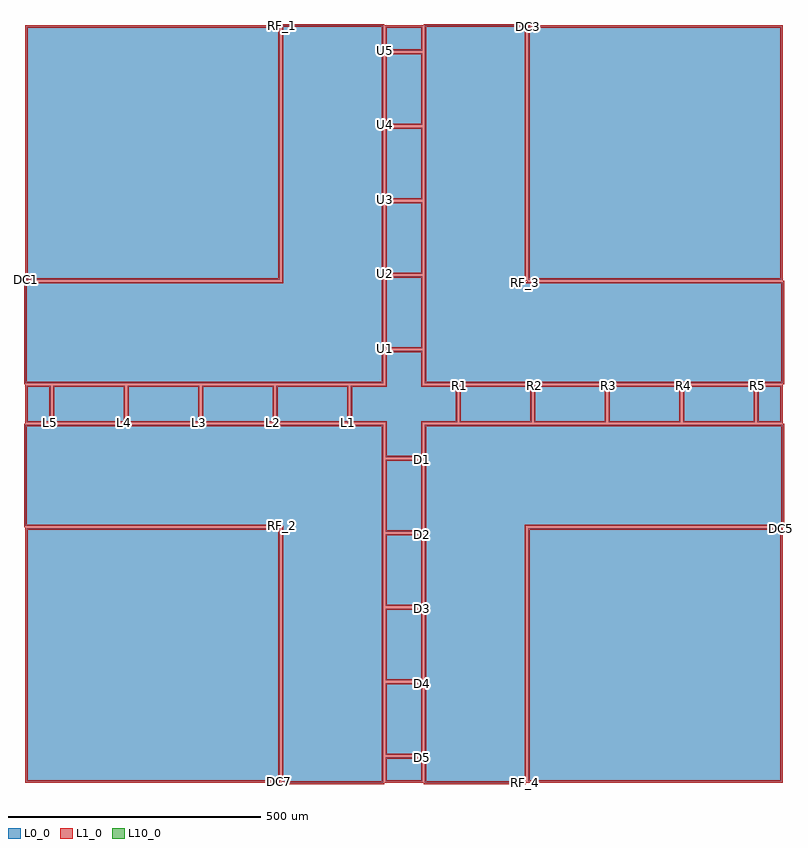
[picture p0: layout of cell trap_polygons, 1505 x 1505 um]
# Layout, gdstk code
import gdstk
lib = gdstk.Library(unit=1e-6, precision=1e-09)
def P(c, l, *ps):  # polygons
    for p in ps: c.add(gdstk.Polygon(p, *l))
L0_0 = (0, 0)
L1_0 = (1, 0)
L10_0 = (10, 0)

trap_polygons = lib.new_cell('trap_polygons')
P(trap_polygons, L0_0, [(-246.5,-747.5),(-747.5,-747.5),(-747.5,-246.5),(-246.5,-246.5),(-246.5,-747.5)],
  [(747.5,-246.5),(747.5,-747.5),(246.5,-747.5),(246.5,-246.5),(747.5,-246.5)],
  [(246.5,747.5),(747.5,747.5),(747.5,246.5),(246.5,246.5),(246.5,747.5)],
  [(-747.5,246.5),(-747.5,747.5),(-246.5,747.5),(-246.5,246.5),(-747.5,246.5)],
  [(-36.5,700),(-36.5,747.5),(36.5,747.5),(36.5,700),(-36.5,700)],
  [(700,36.5),(747.5,36.5),(747.5,-36.5),(700,-36.5),(700,36.5)],
  [(36.5,-700),(36.5,-747.5),(-36.5,-747.5),(-36.5,-700),(36.5,-700)],
  [(-700,-36.5),(-747.5,-36.5),(-747.5,36.5),(-700,36.5),(-700,-36.5)],
  [(-36.5,552.5),(-36.5,695),(36.5,695),(36.5,552.5),(-36.5,552.5)],
  [(552.5,36.5),(695,36.5),(695,-36.5),(552.5,-36.5),(552.5,36.5)],
  [(36.5,-552.5),(36.5,-695),(-36.5,-695),(-36.5,-552.5),(36.5,-552.5)],
  [(-552.5,-36.5),(-695,-36.5),(-695,36.5),(-552.5,36.5),(-552.5,-36.5)],
  [(-36.5,405),(-36.5,547.5),(36.5,547.5),(36.5,405),(-36.5,405)],
  [(405,36.5),(547.5,36.5),(547.5,-36.5),(405,-36.5),(405,36.5)],
  [(36.5,-405),(36.5,-547.5),(-36.5,-547.5),(-36.5,-405),(36.5,-405)],
  [(-405,-36.5),(-547.5,-36.5),(-547.5,36.5),(-405,36.5),(-405,-36.5)],
  [(-36.5,257.5),(-36.5,400),(36.5,400),(36.5,257.5),(-36.5,257.5)],
  [(257.5,36.5),(400,36.5),(400,-36.5),(257.5,-36.5),(257.5,36.5)],
  [(36.5,-257.5),(36.5,-400),(-36.5,-400),(-36.5,-257.5),(36.5,-257.5)],
  [(-257.5,-36.5),(-400,-36.5),(-400,36.5),(-257.5,36.5),(-257.5,-36.5)],
  [(-36.5,110),(-36.5,252.5),(36.5,252.5),(36.5,110),(-36.5,110)],
  [(110,36.5),(252.5,36.5),(252.5,-36.5),(110,-36.5),(110,36.5)],
  [(36.5,-110),(36.5,-252.5),(-36.5,-252.5),(-36.5,-110),(36.5,-110)],
  [(-110,-36.5),(-252.5,-36.5),(-252.5,36.5),(-110,36.5),(-110,-36.5)],
  [(-36.5,105),(36.5,105),(36.5,36.5),(105,36.5),(105,-36.5),(36.5,-36.5),(36.5,-105),(-36.5,-105),(-36.5,-36.5),(-105,-36.5),(-105,36.5),(-36.5,36.5),(-36.5,105)],
  [(241.5,-750),(41.5,-750),(41.5,-41.5),(750,-41.5),(750,-241.5),(241.5,-241.5),(241.5,-750)],
  [(241.5,241.5),(750,241.5),(750,41.5),(41.5,41.5),(41.5,750),(241.5,750),(241.5,241.5)],
  [(-241.5,-241.5),(-750,-241.5),(-750,-41.5),(-41.5,-41.5),(-41.5,-750),(-241.5,-750),(-241.5,-241.5)],
  [(-241.5,750),(-41.5,750),(-41.5,41.5),(-750,41.5),(-750,241.5),(-241.5,241.5),(-241.5,750)])
P(trap_polygons, L1_0, [(-246.5,-750),(-246.5,-745),(-745,-745),(-745,-249),(-249,-249),(-249,-747.5),(-244,-747.5),(-244,-244),(-750,-244),(-750,-750)],
  [(750,-246.5),(745,-246.5),(745,-745),(249,-745),(249,-249),(747.5,-249),(747.5,-244),(244,-244),(244,-750),(750,-750)],
  [(246.5,750),(246.5,745),(745,745),(745,249),(249,249),(249,747.5),(244,747.5),(244,244),(750,244),(750,750)],
  [(-750,246.5),(-745,246.5),(-745,745),(-249,745),(-249,249),(-747.5,249),(-747.5,244),(-244,244),(-244,750),(-750,750)],
  [(-39,700),(-34,700),(-34,745),(34,745),(34,702.5),(-36.5,702.5),(-36.5,697.5),(39,697.5),(39,750),(-39,750)],
  [(700,39),(700,34),(745,34),(745,-34),(702.5,-34),(702.5,36.5),(697.5,36.5),(697.5,-39),(750,-39),(750,39)],
  [(39,-700),(34,-700),(34,-745),(-34,-745),(-34,-702.5),(36.5,-702.5),(36.5,-697.5),(-39,-697.5),(-39,-750),(39,-750)],
  [(-700,-39),(-700,-34),(-745,-34),(-745,34),(-702.5,34),(-702.5,-36.5),(-697.5,-36.5),(-697.5,39),(-750,39),(-750,-39)],
  [(-39,552.5),(-34,552.5),(-34,692.5),(34,692.5),(34,555),(-36.5,555),(-36.5,550),(39,550),(39,697.5),(-39,697.5)],
  [(552.5,39),(552.5,34),(692.5,34),(692.5,-34),(555,-34),(555,36.5),(550,36.5),(550,-39),(697.5,-39),(697.5,39)],
  [(39,-552.5),(34,-552.5),(34,-692.5),(-34,-692.5),(-34,-555),(36.5,-555),(36.5,-550),(-39,-550),(-39,-697.5),(39,-697.5)],
  [(-552.5,-39),(-552.5,-34),(-692.5,-34),(-692.5,34),(-555,34),(-555,-36.5),(-550,-36.5),(-550,39),(-697.5,39),(-697.5,-39)],
  [(-39,405),(-34,405),(-34,545),(34,545),(34,407.5),(-36.5,407.5),(-36.5,402.5),(39,402.5),(39,550),(-39,550)],
  [(405,39),(405,34),(545,34),(545,-34),(407.5,-34),(407.5,36.5),(402.5,36.5),(402.5,-39),(550,-39),(550,39)],
  [(39,-405),(34,-405),(34,-545),(-34,-545),(-34,-407.5),(36.5,-407.5),(36.5,-402.5),(-39,-402.5),(-39,-550),(39,-550)],
  [(-405,-39),(-405,-34),(-545,-34),(-545,34),(-407.5,34),(-407.5,-36.5),(-402.5,-36.5),(-402.5,39),(-550,39),(-550,-39)],
  [(-39,257.5),(-34,257.5),(-34,397.5),(34,397.5),(34,260),(-36.5,260),(-36.5,255),(39,255),(39,402.5),(-39,402.5)],
  [(257.5,39),(257.5,34),(397.5,34),(397.5,-34),(260,-34),(260,36.5),(255,36.5),(255,-39),(402.5,-39),(402.5,39)],
  [(39,-257.5),(34,-257.5),(34,-397.5),(-34,-397.5),(-34,-260),(36.5,-260),(36.5,-255),(-39,-255),(-39,-402.5),(39,-402.5)],
  [(-257.5,-39),(-257.5,-34),(-397.5,-34),(-397.5,34),(-260,34),(-260,-36.5),(-255,-36.5),(-255,39),(-402.5,39),(-402.5,-39)],
  [(-39,110),(-34,110),(-34,250),(34,250),(34,112.5),(-36.5,112.5),(-36.5,107.5),(39,107.5),(39,255),(-39,255)],
  [(110,39),(110,34),(250,34),(250,-34),(112.5,-34),(112.5,36.5),(107.5,36.5),(107.5,-39),(255,-39),(255,39)],
  [(39,-110),(34,-110),(34,-250),(-34,-250),(-34,-112.5),(36.5,-112.5),(36.5,-107.5),(-39,-107.5),(-39,-255),(39,-255)],
  [(-110,-39),(-110,-34),(-250,-34),(-250,34),(-112.5,34),(-112.5,-36.5),(-107.5,-36.5),(-107.5,39),(-255,39),(-255,-39)],
  [(-36.5,107.5),(-36.5,102.5),(34,102.5),(34,34),(102.5,34),(102.5,-34),(34,-34),(34,-102.5),(-34,-102.5),(-34,-34),(-102.5,-34),(-102.5,34),(-34,34),(-34,105),(-39,105),(-39,39),(-107.5,39),(-107.5,-39),(-39,-39),(-39,-107.5),(39,-107.5),(39,-39),(107.5,-39),(107.5,39),(39,39),(39,107.5)],
  [(241.5,-752.5),(241.5,-747.5),(44,-747.5),(44,-44),(747.5,-44),(747.5,-239),(239,-239),(239,-750),(244,-750),(244,-244),(752.5,-244),(752.5,-39),(39,-39),(39,-752.5)],
  [(241.5,244),(241.5,239),(747.5,239),(747.5,44),(44,44),(44,747.5),(239,747.5),(239,241.5),(244,241.5),(244,752.5),(39,752.5),(39,39),(752.5,39),(752.5,244)],
  [(-241.5,-244),(-241.5,-239),(-747.5,-239),(-747.5,-44),(-44,-44),(-44,-747.5),(-239,-747.5),(-239,-241.5),(-244,-241.5),(-244,-752.5),(-39,-752.5),(-39,-39),(-752.5,-39),(-752.5,-244)],
  [(-241.5,752.5),(-241.5,747.5),(-44,747.5),(-44,44),(-747.5,44),(-747.5,239),(-239,239),(-239,750),(-244,750),(-244,244),(-752.5,244),(-752.5,39),(-39,39),(-39,752.5)])
P(trap_polygons, L10_0, [(0,0),(0,0),(0,0),(0,0)])
trap_polygons.add(gdstk.Label('DC7', (-246.5,-747.5), layer=2, texttype=0))
trap_polygons.add(gdstk.Label('DC5', (747.5,-246.5), layer=2, texttype=0))
trap_polygons.add(gdstk.Label('DC3', (246.5,747.5), layer=2, texttype=0))
trap_polygons.add(gdstk.Label('DC1', (-747.5,246.5), layer=2, texttype=0))
trap_polygons.add(gdstk.Label('U5', (-36.5,700), layer=2, texttype=0))
trap_polygons.add(gdstk.Label('R5', (700,36.5), layer=2, texttype=0))
trap_polygons.add(gdstk.Label('D5', (36.5,-700), layer=2, texttype=0))
trap_polygons.add(gdstk.Label('L5', (-700,-36.5), layer=2, texttype=0))
trap_polygons.add(gdstk.Label('U4', (-36.5,552.5), layer=2, texttype=0))
trap_polygons.add(gdstk.Label('R4', (552.5,36.5), layer=2, texttype=0))
trap_polygons.add(gdstk.Label('D4', (36.5,-552.5), layer=2, texttype=0))
trap_polygons.add(gdstk.Label('L4', (-552.5,-36.5), layer=2, texttype=0))
trap_polygons.add(gdstk.Label('U3', (-36.5,405), layer=2, texttype=0))
trap_polygons.add(gdstk.Label('R3', (405,36.5), layer=2, texttype=0))
trap_polygons.add(gdstk.Label('D3', (36.5,-405), layer=2, texttype=0))
trap_polygons.add(gdstk.Label('L3', (-405,-36.5), layer=2, texttype=0))
trap_polygons.add(gdstk.Label('U2', (-36.5,257.5), layer=2, texttype=0))
trap_polygons.add(gdstk.Label('R2', (257.5,36.5), layer=2, texttype=0))
trap_polygons.add(gdstk.Label('D2', (36.5,-257.5), layer=2, texttype=0))
trap_polygons.add(gdstk.Label('L2', (-257.5,-36.5), layer=2, texttype=0))
trap_polygons.add(gdstk.Label('U1', (-36.5,110), layer=2, texttype=0))
trap_polygons.add(gdstk.Label('R1', (110,36.5), layer=2, texttype=0))
trap_polygons.add(gdstk.Label('D1', (36.5,-110), layer=2, texttype=0))
trap_polygons.add(gdstk.Label('L1', (-110,-36.5), layer=2, texttype=0))
trap_polygons.add(gdstk.Label('C', (-36.5,105), layer=2, texttype=0))
trap_polygons.add(gdstk.Label('RF_4', (241.5,-750), layer=2, texttype=0))
trap_polygons.add(gdstk.Label('RF_3', (241.5,241.5), layer=2, texttype=0))
trap_polygons.add(gdstk.Label('RF_2', (-241.5,-241.5), layer=2, texttype=0))
trap_polygons.add(gdstk.Label('RF_1', (-241.5,750), layer=2, texttype=0))

lib.write_gds('trap_polygons.gds')
